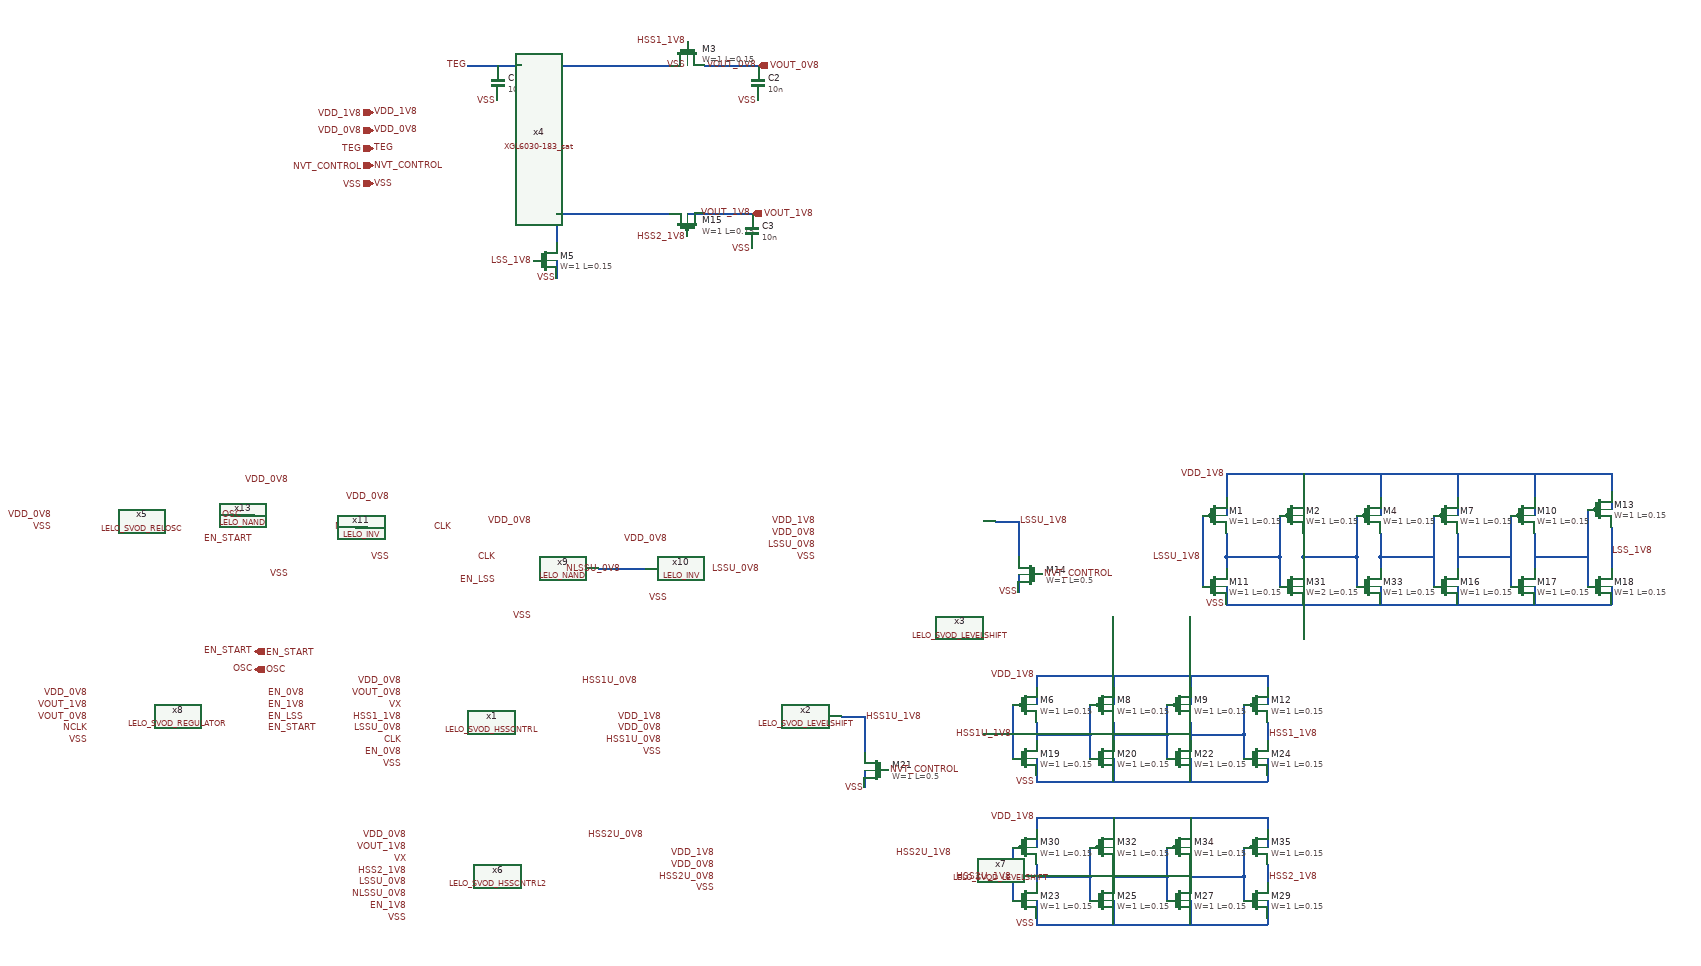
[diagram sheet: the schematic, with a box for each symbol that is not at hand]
v {xschem version=3.4.8RC file_version=1.2}
G {}
K {}
V {}
S {}
E {}
N -350 -940 -290 -940 {lab=VX}
N -480 -940 -350 -940 {lab=VX}
N -480 -940 -480 -780 {lab=VX}
N -560 -940 -540 -940 {lab=TEG}
N 650 -60 650 -30 {lab=VSS}
N 1040 -150 1040 -90 {lab=#net1}
N 1040 -60 1040 -30 {lab=VSS}
N 1000 -180 1000 -60 {lab=#net2}
N 650 -110 740 -110 {lab=#net3}
N -580 -940 -560 -940 {lab=TEG}
N 1170 -150 1170 -90 {lab=#net4}
N 1170 -60 1170 -30 {lab=VSS}
N 1130 -180 1130 -60 {lab=#net1}
N 1040 -110 1130 -110 {lab=#net1}
N 1300 -160 1300 -90 {lab=LSS_1V8}
N 1300 -60 1300 -30 {lab=VSS}
N 1260 -190 1260 -60 {lab=#net4}
N 1170 -110 1260 -110 {lab=#net4}
N -230 -940 -140 -940 {lab=VOUT_0V8}
N 650 -250 1230 -250 {lab=VDD_1V8}
N 1040 -250 1040 -210 {lab=VDD_1V8}
N 1170 -250 1170 -210 {lab=VDD_1V8}
N 1300 -250 1300 -220 {lab=VDD_1V8}
N 650 -250 650 -210 {lab=VDD_1V8}
N 650 -150 650 -110 {lab=#net3}
N 650 -110 650 -90 {lab=#net3}
N 610 -180 610 -110 {lab=LSSU_1V8}
N 610 -110 610 -60 {lab=LSSU_1V8}
N 330 90 330 110 {lab=VDD_1V8}
N 460 90 460 110 {lab=VDD_1V8}
N 330 230 330 260 {lab=VSS}
N 460 230 460 260 {lab=VSS}
N 290 140 290 190 {lab=HSS1U_1V8}
N 290 190 290 230 {lab=HSS1U_1V8}
N 330 170 330 200 {lab=#net5}
N 330 260 330 270 {lab=VSS}
N 330 190 420 190 {lab=#net5}
N 420 140 420 190 {lab=#net5}
N 420 190 420 230 {lab=#net5}
N 460 170 460 200 {lab=#net6}
N 460 260 460 270 {lab=VSS}
N 590 90 590 110 {lab=VDD_1V8}
N 590 230 590 260 {lab=VSS}
N 460 190 550 190 {lab=#net6}
N 550 140 550 190 {lab=#net6}
N 550 190 550 230 {lab=#net6}
N 590 170 590 200 {lab=#net7}
N 590 260 590 270 {lab=VSS}
N 720 90 720 110 {lab=VDD_1V8}
N 720 230 720 260 {lab=VSS}
N 680 140 680 190 {lab=#net7}
N 680 190 680 230 {lab=#net7}
N 720 170 720 200 {lab=HSS1_1V8}
N 720 260 720 270 {lab=VSS}
N 650 -210 650 -180 {lab=VDD_1V8}
N 1040 -210 1040 -180 {lab=VDD_1V8}
N 1170 -210 1170 -180 {lab=VDD_1V8}
N 1300 -220 1300 -190 {lab=VDD_1V8}
N 330 110 330 140 {lab=VDD_1V8}
N 460 110 460 140 {lab=VDD_1V8}
N 590 110 590 140 {lab=VDD_1V8}
N 780 -60 780 -30 {lab=VSS}
N 780 -110 870 -110 {lab=#net8}
N 780 -250 780 -210 {lab=VDD_1V8}
N 780 -150 780 -110 {lab=#net8}
N 780 -110 780 -90 {lab=#net8}
N 740 -180 740 -110 {lab=#net3}
N 740 -110 740 -60 {lab=#net3}
N 780 -210 780 -180 {lab=VDD_1V8}
N 910 -60 910 -30 {lab=VSS}
N 910 -110 1000 -110 {lab=#net2}
N 910 -250 910 -210 {lab=VDD_1V8}
N 910 -150 910 -110 {lab=#net2}
N 910 -110 910 -90 {lab=#net2}
N 870 -180 870 -110 {lab=#net8}
N 870 -110 870 -60 {lab=#net8}
N 910 -210 910 -180 {lab=VDD_1V8}
N 590 190 680 190 {lab=#net7}
N -480 -780 -480 -700 {lab=VX}
N -480 -700 -480 -640 {lab=VX}
N -480 -610 -480 -580 {lab=VSS}
N 330 90 720 90 {lab=VDD_1V8}
N 720 110 720 140 {lab=VDD_1V8}
N 1230 -250 1300 -250 {lab=VDD_1V8}
N 650 -30 1300 -30 {lab=VSS}
N 330 270 720 270 {lab=VSS}
N -480 -690 -290 -690 {lab=VX}
N -260 -690 -230 -690 {lab=VOUT_1V8}
N -230 -690 -150 -690 {lab=VOUT_1V8}
N 330 330 330 350 {lab=VDD_1V8}
N 460 330 460 350 {lab=VDD_1V8}
N 330 470 330 500 {lab=VSS}
N 460 470 460 500 {lab=VSS}
N 290 380 290 430 {lab=HSS2U_1V8}
N 290 430 290 470 {lab=HSS2U_1V8}
N 330 410 330 440 {lab=#net9}
N 330 500 330 510 {lab=VSS}
N 330 430 420 430 {lab=#net9}
N 420 380 420 430 {lab=#net9}
N 420 430 420 470 {lab=#net9}
N 460 410 460 440 {lab=#net10}
N 460 500 460 510 {lab=VSS}
N 590 330 590 350 {lab=VDD_1V8}
N 590 470 590 500 {lab=VSS}
N 460 430 550 430 {lab=#net10}
N 550 380 550 430 {lab=#net10}
N 550 430 550 470 {lab=#net10}
N 590 410 590 440 {lab=#net11}
N 590 500 590 510 {lab=VSS}
N 720 330 720 350 {lab=VDD_1V8}
N 720 470 720 500 {lab=VSS}
N 680 380 680 430 {lab=#net11}
N 680 430 680 470 {lab=#net11}
N 720 410 720 440 {lab=HSS2_1V8}
N 720 500 720 510 {lab=VSS}
N 330 350 330 380 {lab=VDD_1V8}
N 460 350 460 380 {lab=VDD_1V8}
N 590 350 590 380 {lab=VDD_1V8}
N 590 430 680 430 {lab=#net11}
N 330 330 720 330 {lab=VDD_1V8}
N 720 350 720 380 {lab=VDD_1V8}
N 330 510 720 510 {lab=VSS}
N -410 -90 -330 -90 {lab=NLSSU_0V8}
N -820 -160 -800 -160 {lab=NCLK}
N -630 -940 -580 -940 {lab=TEG}
N -1030 -180 -990 -180 {lab=OSC}
N 260 -170 300 -170 {lab=LSSU_1V8}
N 300 -80 300 -50 {lab=VSS}
N 300 -170 300 -110 {lab=LSSU_1V8}
N 0 160 40 160 {lab=LSSU_1V8}
N 40 250 40 280 {lab=VSS}
N 40 160 40 220 {lab=LSSU_1V8}
C {devices/lab_pin.sym} -480 -940 3 1 {name=p3 sig_type=std_logic lab=VX}
C {devices/lab_pin.sym} 1300 -120 0 1 {name=p30 sig_type=std_logic lab=LSS_1V8}
C {devices/capa.sym} -580 -910 0 1 {name=C1
m=1
value=100u
footprint=1206
device="ceramic capacitor"}
C {sky130_fd_pr/nfet_01v8_lvt.sym} -500 -610 0 0 {name=M5
W=1
L=0.15
nf=1
mult=15804
ad="expr('int((@nf + 1)/2) * @W / @nf * 0.29')"
pd="expr('2*int((@nf + 1)/2) * (@W / @nf + 0.29)')"
as="expr('int((@nf + 2)/2) * @W / @nf * 0.29')"
ps="expr('2*int((@nf + 2)/2) * (@W / @nf + 0.29)')"
nrd="expr('0.29 / @W ')" nrs="expr('0.29 / @W ')"
sa=0 sb=0 sd=0
model=nfet_01v8_lvt
spiceprefix=X
}
C {devices/lab_pin.sym} -630 -940 2 1 {name=p93 sig_type=std_logic lab=TEG}
C {devices/capa.sym} -140 -910 0 1 {name=C2
m=1
value=10n
footprint=1206
device="ceramic capacitor"}
C {devices/lab_pin.sym} -140 -940 1 0 {name=p35 sig_type=std_logic lab=VOUT_0V8}
C {sky130_fd_pr/nfet_01v8.sym} 630 -60 0 0 {name=M11
W=1
L=0.15
nf=1 
mult=1
ad="expr('int((@nf + 1)/2) * @W / @nf * 0.29')"
pd="expr('2*int((@nf + 1)/2) * (@W / @nf + 0.29)')"
as="expr('int((@nf + 2)/2) * @W / @nf * 0.29')"
ps="expr('2*int((@nf + 2)/2) * (@W / @nf + 0.29)')"
nrd="expr('0.29 / @W ')" nrs="expr('0.29 / @W ')"
sa=0 sb=0 sd=0
model=nfet_01v8
spiceprefix=X
}
C {sky130_fd_pr/nfet_01v8.sym} 1020 -60 0 0 {name=M16
W=1
L=0.15
nf=1 
mult=27
ad="expr('int((@nf + 1)/2) * @W / @nf * 0.29')"
pd="expr('2*int((@nf + 1)/2) * (@W / @nf + 0.29)')"
as="expr('int((@nf + 2)/2) * @W / @nf * 0.29')"
ps="expr('2*int((@nf + 2)/2) * (@W / @nf + 0.29)')"
nrd="expr('0.29 / @W ')" nrs="expr('0.29 / @W ')"
sa=0 sb=0 sd=0
model=nfet_01v8
spiceprefix=X
}
C {sky130_fd_pr/nfet_01v8.sym} 1150 -60 0 0 {name=M17
W=1
L=0.15
nf=1 
mult=81
ad="expr('int((@nf + 1)/2) * @W / @nf * 0.29')"
pd="expr('2*int((@nf + 1)/2) * (@W / @nf + 0.29)')"
as="expr('int((@nf + 2)/2) * @W / @nf * 0.29')"
ps="expr('2*int((@nf + 2)/2) * (@W / @nf + 0.29)')"
nrd="expr('0.29 / @W ')" nrs="expr('0.29 / @W ')"
sa=0 sb=0 sd=0
model=nfet_01v8
spiceprefix=X
}
C {sky130_fd_pr/nfet_01v8.sym} 1280 -60 0 0 {name=M18
W=1
L=0.15
nf=1 
mult=243
ad="expr('int((@nf + 1)/2) * @W / @nf * 0.29')"
pd="expr('2*int((@nf + 1)/2) * (@W / @nf + 0.29)')"
as="expr('int((@nf + 2)/2) * @W / @nf * 0.29')"
ps="expr('2*int((@nf + 2)/2) * (@W / @nf + 0.29)')"
nrd="expr('0.29 / @W ')" nrs="expr('0.29 / @W ')"
sa=0 sb=0 sd=0
model=nfet_01v8
spiceprefix=X
}
C {sky130_fd_pr/nfet_01v8.sym} 310 230 0 0 {name=M19
W=1
L=0.15
nf=1 
mult=1
ad="expr('int((@nf + 1)/2) * @W / @nf * 0.29')"
pd="expr('2*int((@nf + 1)/2) * (@W / @nf + 0.29)')"
as="expr('int((@nf + 2)/2) * @W / @nf * 0.29')"
ps="expr('2*int((@nf + 2)/2) * (@W / @nf + 0.29)')"
nrd="expr('0.29 / @W ')" nrs="expr('0.29 / @W ')"
sa=0 sb=0 sd=0
model=nfet_01v8
spiceprefix=X
}
C {sky130_fd_pr/nfet_01v8.sym} 440 230 0 0 {name=M20
W=1
L=0.15
nf=1 
mult=3
ad="expr('int((@nf + 1)/2) * @W / @nf * 0.29')"
pd="expr('2*int((@nf + 1)/2) * (@W / @nf + 0.29)')"
as="expr('int((@nf + 2)/2) * @W / @nf * 0.29')"
ps="expr('2*int((@nf + 2)/2) * (@W / @nf + 0.29)')"
nrd="expr('0.29 / @W ')" nrs="expr('0.29 / @W ')"
sa=0 sb=0 sd=0
model=nfet_01v8
spiceprefix=X
}
C {sky130_fd_pr/nfet_01v8.sym} 570 230 0 0 {name=M22
W=1
L=0.15
nf=1 
mult=9
ad="expr('int((@nf + 1)/2) * @W / @nf * 0.29')"
pd="expr('2*int((@nf + 1)/2) * (@W / @nf + 0.29)')"
as="expr('int((@nf + 2)/2) * @W / @nf * 0.29')"
ps="expr('2*int((@nf + 2)/2) * (@W / @nf + 0.29)')"
nrd="expr('0.29 / @W ')" nrs="expr('0.29 / @W ')"
sa=0 sb=0 sd=0
model=nfet_01v8
spiceprefix=X
}
C {sky130_fd_pr/nfet_01v8.sym} 700 230 0 0 {name=M24
W=1
L=0.15
nf=1 
mult=27
ad="expr('int((@nf + 1)/2) * @W / @nf * 0.29')"
pd="expr('2*int((@nf + 1)/2) * (@W / @nf + 0.29)')"
as="expr('int((@nf + 2)/2) * @W / @nf * 0.29')"
ps="expr('2*int((@nf + 2)/2) * (@W / @nf + 0.29)')"
nrd="expr('0.29 / @W ')" nrs="expr('0.29 / @W ')"
sa=0 sb=0 sd=0
model=nfet_01v8
spiceprefix=X
}
C {sky130_fd_pr/nfet_01v8.sym} 760 -60 0 0 {name=M31
W=2
L=0.15
nf=1 
mult=3
ad="expr('int((@nf + 1)/2) * @W / @nf * 0.29')"
pd="expr('2*int((@nf + 1)/2) * (@W / @nf + 0.29)')"
as="expr('int((@nf + 2)/2) * @W / @nf * 0.29')"
ps="expr('2*int((@nf + 2)/2) * (@W / @nf + 0.29)')"
nrd="expr('0.29 / @W ')" nrs="expr('0.29 / @W ')"
sa=0 sb=0 sd=0
model=nfet_01v8
spiceprefix=X
}
C {sky130_fd_pr/nfet_01v8.sym} 890 -60 0 0 {name=M33
W=1
L=0.15
nf=1 
mult=9
ad="expr('int((@nf + 1)/2) * @W / @nf * 0.29')"
pd="expr('2*int((@nf + 1)/2) * (@W / @nf + 0.29)')"
as="expr('int((@nf + 2)/2) * @W / @nf * 0.29')"
ps="expr('2*int((@nf + 2)/2) * (@W / @nf + 0.29)')"
nrd="expr('0.29 / @W ')" nrs="expr('0.29 / @W ')"
sa=0 sb=0 sd=0
model=nfet_01v8
spiceprefix=X
}
C {devices/lab_pin.sym} -260 -980 1 0 {name=p101 sig_type=std_logic lab=HSS1_1V8}
C {sky130_fd_pr/nfet_01v8_lvt.sym} -260 -960 1 0 {name=M3
W=1
L=0.15
nf=1
mult=3244
ad="expr('int((@nf + 1)/2) * @W / @nf * 0.29')"
pd="expr('2*int((@nf + 1)/2) * (@W / @nf + 0.29)')"
as="expr('int((@nf + 2)/2) * @W / @nf * 0.29')"
ps="expr('2*int((@nf + 2)/2) * (@W / @nf + 0.29)')"
nrd="expr('0.29 / @W ')" nrs="expr('0.29 / @W ')"
sa=0 sb=0 sd=0
model=nfet_01v8_lvt
spiceprefix=X
}
C {devices/lab_pin.sym} -220 -90 0 1 {name=p10 sig_type=std_logic lab=LSSU_0V8}
C {LELO_SVOD_SKY130A/LELO_SVOD_HSSCNTRL.sym} -590 170 0 0 {name=x1}
C {devices/lab_pin.sym} -440 100 2 0 {name=p22 sig_type=std_logic lab=HSS1U_0V8}
C {devices/lab_pin.sym} -740 140 2 1 {name=p26 sig_type=std_logic lab=VX}
C {devices/lab_pin.sym} -740 120 0 0 {name=p27 sig_type=std_logic lab=VOUT_0V8}
C {LELO_SVOD_SKY130A/LELO_SVOD_LEVELSHIFT.sym} -150 190 0 0 {name=x2}
C {LELO_SVOD_SKY130A/LELO_SVOD_LEVELSHIFT.sym} 110 -140 0 0 {name=x3}
C {devices/lab_pin.sym} 40 160 2 0 {name=p8 sig_type=std_logic lab=HSS1U_1V8}
C {devices/lab_pin.sym} 300 -170 0 1 {name=p23 sig_type=std_logic lab=LSSU_1V8}
C {sky130_fd_pr/pfet_01v8_hvt.sym} 310 140 0 0 {name=M6
W=1
L=0.15
nf=1
mult=1
ad="expr('int((@nf + 1)/2) * @W / @nf * 0.29')"
pd="expr('2*int((@nf + 1)/2) * (@W / @nf + 0.29)')"
as="expr('int((@nf + 2)/2) * @W / @nf * 0.29')"
ps="expr('2*int((@nf + 2)/2) * (@W / @nf + 0.29)')"
nrd="expr('0.29 / @W ')" nrs="expr('0.29 / @W ')"
sa=0 sb=0 sd=0
model=pfet_01v8_hvt
spiceprefix=X
}
C {sky130_fd_pr/pfet_01v8_hvt.sym} 440 140 0 0 {name=M8
W=1
L=0.15
nf=1
mult=3
ad="expr('int((@nf + 1)/2) * @W / @nf * 0.29')"
pd="expr('2*int((@nf + 1)/2) * (@W / @nf + 0.29)')"
as="expr('int((@nf + 2)/2) * @W / @nf * 0.29')"
ps="expr('2*int((@nf + 2)/2) * (@W / @nf + 0.29)')"
nrd="expr('0.29 / @W ')" nrs="expr('0.29 / @W ')"
sa=0 sb=0 sd=0
model=pfet_01v8_hvt
spiceprefix=X
}
C {sky130_fd_pr/pfet_01v8_hvt.sym} 570 140 0 0 {name=M9
W=1
L=0.15
nf=1
mult=9
ad="expr('int((@nf + 1)/2) * @W / @nf * 0.29')"
pd="expr('2*int((@nf + 1)/2) * (@W / @nf + 0.29)')"
as="expr('int((@nf + 2)/2) * @W / @nf * 0.29')"
ps="expr('2*int((@nf + 2)/2) * (@W / @nf + 0.29)')"
nrd="expr('0.29 / @W ')" nrs="expr('0.29 / @W ')"
sa=0 sb=0 sd=0
model=pfet_01v8_hvt
spiceprefix=X
}
C {sky130_fd_pr/pfet_01v8_hvt.sym} 700 140 0 0 {name=M12
W=1
L=0.15
nf=1
mult=27
ad="expr('int((@nf + 1)/2) * @W / @nf * 0.29')"
pd="expr('2*int((@nf + 1)/2) * (@W / @nf + 0.29)')"
as="expr('int((@nf + 2)/2) * @W / @nf * 0.29')"
ps="expr('2*int((@nf + 2)/2) * (@W / @nf + 0.29)')"
nrd="expr('0.29 / @W ')" nrs="expr('0.29 / @W ')"
sa=0 sb=0 sd=0
model=pfet_01v8_hvt
spiceprefix=X
}
C {sky130_fd_pr/pfet_01v8_hvt.sym} 630 -180 0 0 {name=M1
W=1
L=0.15
nf=1
mult=1
ad="expr('int((@nf + 1)/2) * @W / @nf * 0.29')"
pd="expr('2*int((@nf + 1)/2) * (@W / @nf + 0.29)')"
as="expr('int((@nf + 2)/2) * @W / @nf * 0.29')"
ps="expr('2*int((@nf + 2)/2) * (@W / @nf + 0.29)')"
nrd="expr('0.29 / @W ')" nrs="expr('0.29 / @W ')"
sa=0 sb=0 sd=0
model=pfet_01v8_hvt
spiceprefix=X
}
C {sky130_fd_pr/pfet_01v8_hvt.sym} 760 -180 0 0 {name=M2
W=1
L=0.15
nf=1
mult=3
ad="expr('int((@nf + 1)/2) * @W / @nf * 0.29')"
pd="expr('2*int((@nf + 1)/2) * (@W / @nf + 0.29)')"
as="expr('int((@nf + 2)/2) * @W / @nf * 0.29')"
ps="expr('2*int((@nf + 2)/2) * (@W / @nf + 0.29)')"
nrd="expr('0.29 / @W ')" nrs="expr('0.29 / @W ')"
sa=0 sb=0 sd=0
model=pfet_01v8_hvt
spiceprefix=X
}
C {sky130_fd_pr/pfet_01v8_hvt.sym} 890 -180 0 0 {name=M4
W=1
L=0.15
nf=1
mult=9
ad="expr('int((@nf + 1)/2) * @W / @nf * 0.29')"
pd="expr('2*int((@nf + 1)/2) * (@W / @nf + 0.29)')"
as="expr('int((@nf + 2)/2) * @W / @nf * 0.29')"
ps="expr('2*int((@nf + 2)/2) * (@W / @nf + 0.29)')"
nrd="expr('0.29 / @W ')" nrs="expr('0.29 / @W ')"
sa=0 sb=0 sd=0
model=pfet_01v8_hvt
spiceprefix=X
}
C {sky130_fd_pr/pfet_01v8_hvt.sym} 1020 -180 0 0 {name=M7
W=1
L=0.15
nf=1
mult=27
ad="expr('int((@nf + 1)/2) * @W / @nf * 0.29')"
pd="expr('2*int((@nf + 1)/2) * (@W / @nf + 0.29)')"
as="expr('int((@nf + 2)/2) * @W / @nf * 0.29')"
ps="expr('2*int((@nf + 2)/2) * (@W / @nf + 0.29)')"
nrd="expr('0.29 / @W ')" nrs="expr('0.29 / @W ')"
sa=0 sb=0 sd=0
model=pfet_01v8_hvt
spiceprefix=X
}
C {sky130_fd_pr/pfet_01v8_hvt.sym} 1150 -180 0 0 {name=M10
W=1
L=0.15
nf=1
mult=81
ad="expr('int((@nf + 1)/2) * @W / @nf * 0.29')"
pd="expr('2*int((@nf + 1)/2) * (@W / @nf + 0.29)')"
as="expr('int((@nf + 2)/2) * @W / @nf * 0.29')"
ps="expr('2*int((@nf + 2)/2) * (@W / @nf + 0.29)')"
nrd="expr('0.29 / @W ')" nrs="expr('0.29 / @W ')"
sa=0 sb=0 sd=0
model=pfet_01v8_hvt
spiceprefix=X
}
C {sky130_fd_pr/pfet_01v8_hvt.sym} 1280 -190 0 0 {name=M13
W=1
L=0.15
nf=1
mult=243
ad="expr('int((@nf + 1)/2) * @W / @nf * 0.29')"
pd="expr('2*int((@nf + 1)/2) * (@W / @nf + 0.29)')"
as="expr('int((@nf + 2)/2) * @W / @nf * 0.29')"
ps="expr('2*int((@nf + 2)/2) * (@W / @nf + 0.29)')"
nrd="expr('0.29 / @W ')" nrs="expr('0.29 / @W ')"
sa=0 sb=0 sd=0
model=pfet_01v8_hvt
spiceprefix=X
}
C {devices/lab_pin.sym} -300 200 2 1 {name=p5 sig_type=std_logic lab=HSS1U_0V8}
C {devices/lab_pin.sym} 290 190 2 1 {name=p9 sig_type=std_logic lab=HSS1U_1V8}
C {devices/lab_pin.sym} -1330 -180 0 0 {name=p17 sig_type=std_logic lab=VDD_0V8}
C {devices/lab_pin.sym} -740 100 0 0 {name=p21 sig_type=std_logic lab=VDD_0V8}
C {devices/lab_pin.sym} -300 180 0 0 {name=p28 sig_type=std_logic lab=VDD_0V8}
C {devices/lab_pin.sym} -40 -150 0 0 {name=p29 sig_type=std_logic lab=VDD_0V8}
C {devices/lab_pin.sym} -300 160 0 0 {name=p31 sig_type=std_logic lab=VDD_1V8}
C {devices/lab_pin.sym} -40 -170 0 0 {name=p32 sig_type=std_logic lab=VDD_1V8}
C {devices/lab_pin.sym} 330 90 0 0 {name=p33 sig_type=std_logic lab=VDD_1V8}
C {devices/lab_pin.sym} 650 -250 0 0 {name=p34 sig_type=std_logic lab=VDD_1V8}
C {devices/lab_pin.sym} -520 -610 0 0 {name=p36 sig_type=std_logic lab=LSS_1V8}
C {devices/lab_pin.sym} -40 -130 0 0 {name=p37 sig_type=std_logic lab=LSSU_0V8}
C {devices/lab_pin.sym} 610 -110 0 0 {name=p38 sig_type=std_logic lab=LSSU_1V8}
C {devices/lab_pin.sym} 720 190 2 0 {name=p39 sig_type=std_logic lab=HSS1_1V8}
C {devices/ipin.sym} -790 -740 0 0 {name=p40 lab=VSS}
C {devices/lab_pin.sym} -790 -740 2 0 {name=p41 sig_type=std_logic lab=VSS}
C {devices/lab_pin.sym} -740 180 0 0 {name=p25 sig_type=std_logic lab=LSSU_0V8}
C {devices/lab_pin.sym} -740 160 0 0 {name=p49 sig_type=std_logic lab=HSS1_1V8}
C {devices/lab_pin.sym} -760 -210 1 0 {name=p51 sig_type=std_logic lab=VDD_0V8}
C {LELO_SVOD_SKY130A/XGL6030-183_sat.sym} -510 -940 1 0 {name=x4}
C {LELO_SVOD_SKY130A/LELO_SVOD_RELOSC.sym} -1180 -170 0 0 {name=x5}
C {sky130_fd_pr/pfet_01v8.sym} -260 -670 1 1 {name=M15
W=1
L=0.15
nf=1
mult=481
ad="expr('int((@nf + 1)/2) * @W / @nf * 0.29')"
pd="expr('2*int((@nf + 1)/2) * (@W / @nf + 0.29)')"
as="expr('int((@nf + 2)/2) * @W / @nf * 0.29')"
ps="expr('2*int((@nf + 2)/2) * (@W / @nf + 0.29)')"
nrd="expr('0.29 / @W ')" nrs="expr('0.29 / @W ')"
sa=0 sb=0 sd=0
model=pfet_01v8
spiceprefix=X
}
C {devices/capa.sym} -150 -660 0 1 {name=C3
m=1
value=10n
footprint=1206
device="ceramic capacitor"}
C {devices/lab_pin.sym} -150 -690 1 0 {name=p45 sig_type=std_logic lab=VOUT_1V8}
C {LELO_SVOD_SKY130A/LELO_SVOD_HSSCNTRL2.sym} -580 430 0 0 {name=x6}
C {devices/lab_pin.sym} -730 400 2 1 {name=p48 sig_type=std_logic lab=VX}
C {devices/lab_pin.sym} -730 360 0 0 {name=p50 sig_type=std_logic lab=VDD_0V8}
C {devices/lab_pin.sym} -730 380 0 0 {name=p53 sig_type=std_logic lab=VOUT_1V8}
C {devices/lab_pin.sym} -730 440 0 0 {name=p54 sig_type=std_logic lab=LSSU_0V8}
C {devices/lab_pin.sym} -430 360 2 0 {name=p57 sig_type=std_logic lab=HSS2U_0V8}
C {LELO_SVOD_SKY130A/LELO_SVOD_LEVELSHIFT.sym} -60 420 0 0 {name=x7}
C {devices/lab_pin.sym} 90 390 2 0 {name=p58 sig_type=std_logic lab=HSS2U_1V8}
C {devices/lab_pin.sym} -210 410 0 0 {name=p61 sig_type=std_logic lab=VDD_0V8}
C {devices/lab_pin.sym} -210 390 0 0 {name=p62 sig_type=std_logic lab=VDD_1V8}
C {devices/lab_pin.sym} -210 430 2 1 {name=p60 sig_type=std_logic lab=HSS2U_0V8}
C {sky130_fd_pr/nfet_01v8.sym} 310 470 0 0 {name=M23
W=1
L=0.15
nf=1 
mult=1
ad="expr('int((@nf + 1)/2) * @W / @nf * 0.29')"
pd="expr('2*int((@nf + 1)/2) * (@W / @nf + 0.29)')"
as="expr('int((@nf + 2)/2) * @W / @nf * 0.29')"
ps="expr('2*int((@nf + 2)/2) * (@W / @nf + 0.29)')"
nrd="expr('0.29 / @W ')" nrs="expr('0.29 / @W ')"
sa=0 sb=0 sd=0
model=nfet_01v8
spiceprefix=X
}
C {sky130_fd_pr/nfet_01v8.sym} 440 470 0 0 {name=M25
W=1
L=0.15
nf=1 
mult=3
ad="expr('int((@nf + 1)/2) * @W / @nf * 0.29')"
pd="expr('2*int((@nf + 1)/2) * (@W / @nf + 0.29)')"
as="expr('int((@nf + 2)/2) * @W / @nf * 0.29')"
ps="expr('2*int((@nf + 2)/2) * (@W / @nf + 0.29)')"
nrd="expr('0.29 / @W ')" nrs="expr('0.29 / @W ')"
sa=0 sb=0 sd=0
model=nfet_01v8
spiceprefix=X
}
C {sky130_fd_pr/nfet_01v8.sym} 570 470 0 0 {name=M27
W=1
L=0.15
nf=1 
mult=9
ad="expr('int((@nf + 1)/2) * @W / @nf * 0.29')"
pd="expr('2*int((@nf + 1)/2) * (@W / @nf + 0.29)')"
as="expr('int((@nf + 2)/2) * @W / @nf * 0.29')"
ps="expr('2*int((@nf + 2)/2) * (@W / @nf + 0.29)')"
nrd="expr('0.29 / @W ')" nrs="expr('0.29 / @W ')"
sa=0 sb=0 sd=0
model=nfet_01v8
spiceprefix=X
}
C {sky130_fd_pr/nfet_01v8.sym} 700 470 0 0 {name=M29
W=1
L=0.15
nf=1 
mult=27
ad="expr('int((@nf + 1)/2) * @W / @nf * 0.29')"
pd="expr('2*int((@nf + 1)/2) * (@W / @nf + 0.29)')"
as="expr('int((@nf + 2)/2) * @W / @nf * 0.29')"
ps="expr('2*int((@nf + 2)/2) * (@W / @nf + 0.29)')"
nrd="expr('0.29 / @W ')" nrs="expr('0.29 / @W ')"
sa=0 sb=0 sd=0
model=nfet_01v8
spiceprefix=X
}
C {sky130_fd_pr/pfet_01v8_hvt.sym} 310 380 0 0 {name=M30
W=1
L=0.15
nf=1
mult=1
ad="expr('int((@nf + 1)/2) * @W / @nf * 0.29')"
pd="expr('2*int((@nf + 1)/2) * (@W / @nf + 0.29)')"
as="expr('int((@nf + 2)/2) * @W / @nf * 0.29')"
ps="expr('2*int((@nf + 2)/2) * (@W / @nf + 0.29)')"
nrd="expr('0.29 / @W ')" nrs="expr('0.29 / @W ')"
sa=0 sb=0 sd=0
model=pfet_01v8_hvt
spiceprefix=X
}
C {sky130_fd_pr/pfet_01v8_hvt.sym} 440 380 0 0 {name=M32
W=1
L=0.15
nf=1
mult=3
ad="expr('int((@nf + 1)/2) * @W / @nf * 0.29')"
pd="expr('2*int((@nf + 1)/2) * (@W / @nf + 0.29)')"
as="expr('int((@nf + 2)/2) * @W / @nf * 0.29')"
ps="expr('2*int((@nf + 2)/2) * (@W / @nf + 0.29)')"
nrd="expr('0.29 / @W ')" nrs="expr('0.29 / @W ')"
sa=0 sb=0 sd=0
model=pfet_01v8_hvt
spiceprefix=X
}
C {sky130_fd_pr/pfet_01v8_hvt.sym} 570 380 0 0 {name=M34
W=1
L=0.15
nf=1
mult=9
ad="expr('int((@nf + 1)/2) * @W / @nf * 0.29')"
pd="expr('2*int((@nf + 1)/2) * (@W / @nf + 0.29)')"
as="expr('int((@nf + 2)/2) * @W / @nf * 0.29')"
ps="expr('2*int((@nf + 2)/2) * (@W / @nf + 0.29)')"
nrd="expr('0.29 / @W ')" nrs="expr('0.29 / @W ')"
sa=0 sb=0 sd=0
model=pfet_01v8_hvt
spiceprefix=X
}
C {sky130_fd_pr/pfet_01v8_hvt.sym} 700 380 0 0 {name=M35
W=1
L=0.15
nf=1
mult=27
ad="expr('int((@nf + 1)/2) * @W / @nf * 0.29')"
pd="expr('2*int((@nf + 1)/2) * (@W / @nf + 0.29)')"
as="expr('int((@nf + 2)/2) * @W / @nf * 0.29')"
ps="expr('2*int((@nf + 2)/2) * (@W / @nf + 0.29)')"
nrd="expr('0.29 / @W ')" nrs="expr('0.29 / @W ')"
sa=0 sb=0 sd=0
model=pfet_01v8_hvt
spiceprefix=X
}
C {devices/lab_pin.sym} 330 330 0 0 {name=p65 sig_type=std_logic lab=VDD_1V8}
C {devices/lab_pin.sym} 720 430 2 0 {name=p66 sig_type=std_logic lab=HSS2_1V8}
C {devices/lab_pin.sym} 290 430 2 1 {name=p64 sig_type=std_logic lab=HSS2U_1V8}
C {devices/lab_pin.sym} -730 420 2 1 {name=p67 sig_type=std_logic lab=HSS2_1V8}
C {devices/lab_pin.sym} -260 -650 1 1 {name=p68 sig_type=std_logic lab=HSS2_1V8}
C {LELO_SVOD_SKY130A/LELO_SVOD_REGULATOR.sym} -1120 160 0 0 {name=x8}
C {devices/lab_pin.sym} -970 120 0 1 {name=p18 sig_type=std_logic lab=EN_0V8}
C {devices/lab_pin.sym} -740 220 0 0 {name=p55 sig_type=std_logic lab=EN_0V8}
C {devices/lab_pin.sym} -970 140 0 1 {name=p69 sig_type=std_logic lab=EN_1V8}
C {devices/lab_pin.sym} -730 480 0 0 {name=p70 sig_type=std_logic lab=EN_1V8}
C {devices/lab_pin.sym} -1270 160 0 0 {name=p71 sig_type=std_logic lab=VOUT_0V8}
C {devices/lab_pin.sym} -1270 140 0 0 {name=p72 sig_type=std_logic lab=VOUT_1V8}
C {devices/lab_pin.sym} -1270 120 0 0 {name=p46 sig_type=std_logic lab=VDD_0V8}
C {devices/lab_pin.sym} -810 -160 3 1 {name=p76 sig_type=std_logic lab=NCLK}
C {LELO_SVOD_SKY130A/LELO_NAND.sym} -500 -90 0 0 {name=x9}
C {LELO_SVOD_SKY130A/LELO_INV.sym} -270 -90 0 0 {name=x10}
C {devices/lab_pin.sym} -520 -170 0 0 {name=p81 sig_type=std_logic lab=VDD_0V8}
C {devices/lab_pin.sym} -290 -140 0 0 {name=p82 sig_type=std_logic lab=VDD_0V8}
C {devices/lab_pin.sym} -970 160 0 1 {name=p85 sig_type=std_logic lab=EN_LSS}
C {devices/lab_pin.sym} -580 -70 0 0 {name=p83 sig_type=std_logic lab=EN_LSS}
C {devices/lab_pin.sym} -1270 180 0 0 {name=p74 sig_type=std_logic lab=NCLK}
C {devices/lab_pin.sym} -690 -160 0 1 {name=p84 sig_type=std_logic lab=CLK}
C {devices/lab_pin.sym} -580 -110 0 0 {name=p78 sig_type=std_logic lab=CLK}
C {devices/lab_pin.sym} -370 -90 1 1 {name=p86 sig_type=std_logic lab=NLSSU_0V8}
C {devices/lab_pin.sym} -730 460 2 1 {name=p88 sig_type=std_logic lab=NLSSU_0V8}
C {devices/lab_pin.sym} -740 200 0 0 {name=p87 sig_type=std_logic lab=CLK}
C {devices/lab_pin.sym} -480 -580 3 0 {name=p1 sig_type=std_logic lab=VSS}
C {devices/lab_pin.sym} -150 -630 3 0 {name=p4 sig_type=std_logic lab=VSS}
C {devices/lab_pin.sym} -140 -880 3 0 {name=p11 sig_type=std_logic lab=VSS}
C {devices/lab_pin.sym} -520 -10 3 0 {name=p12 sig_type=std_logic lab=VSS}
C {devices/lab_pin.sym} -760 -110 3 0 {name=p13 sig_type=std_logic lab=VSS}
C {LELO_SVOD_SKY130A/LELO_INV.sym} -740 -160 0 0 {name=x11}
C {devices/lab_pin.sym} -1270 200 0 0 {name=p14 sig_type=std_logic lab=VSS}
C {devices/lab_pin.sym} -740 240 0 0 {name=p15 sig_type=std_logic lab=VSS}
C {devices/lab_pin.sym} -730 500 0 0 {name=p16 sig_type=std_logic lab=VSS}
C {devices/lab_pin.sym} -210 450 0 0 {name=p19 sig_type=std_logic lab=VSS}
C {devices/lab_pin.sym} -300 220 0 0 {name=p20 sig_type=std_logic lab=VSS}
C {devices/lab_pin.sym} -40 -110 0 0 {name=p24 sig_type=std_logic lab=VSS}
C {devices/lab_pin.sym} 330 270 0 0 {name=p42 sig_type=std_logic lab=VSS}
C {devices/lab_pin.sym} 330 510 0 0 {name=p43 sig_type=std_logic lab=VSS}
C {devices/lab_pin.sym} 650 -30 0 0 {name=p44 sig_type=std_logic lab=VSS}
C {devices/lab_pin.sym} -1330 -160 0 0 {name=p47 sig_type=std_logic lab=VSS}
C {devices/lab_pin.sym} -580 -880 3 0 {name=p7 sig_type=std_logic lab=VSS}
C {devices/lab_pin.sym} -260 -940 3 0 {name=p6 sig_type=std_logic lab=VSS}
C {devices/lab_pin.sym} -290 -40 3 0 {name=p52 sig_type=std_logic lab=VSS}
C {devices/ipin.sym} -790 -800 0 0 {name=p56 lab=TEG}
C {devices/lab_pin.sym} -790 -800 2 0 {name=p59 sig_type=std_logic lab=TEG}
C {devices/lab_pin.sym} -790 -830 0 1 {name=p63 sig_type=std_logic lab=VDD_0V8}
C {devices/ipin.sym} -790 -830 0 0 {name=p73 lab=VDD_0V8}
C {devices/lab_pin.sym} -790 -860 0 1 {name=p75 sig_type=std_logic lab=VDD_1V8}
C {devices/ipin.sym} -790 -860 0 0 {name=p77 lab=VDD_1V8}
C {devices/opin.sym} -140 -940 0 0 {name=p2 lab=VOUT_0V8}
C {devices/opin.sym} -150 -690 0 0 {name=p79 lab=VOUT_1V8}
C {LELO_SVOD_SKY130A/LELO_NAND.sym} -910 -160 0 0 {name=x13}
C {devices/lab_pin.sym} -930 -240 0 0 {name=p80 sig_type=std_logic lab=VDD_0V8}
C {devices/lab_pin.sym} -930 -80 3 0 {name=p89 sig_type=std_logic lab=VSS}
C {devices/lab_pin.sym} -1010 -180 3 1 {name=p90 sig_type=std_logic lab=OSC}
C {devices/lab_pin.sym} -990 -140 0 0 {name=p91 sig_type=std_logic lab=EN_START}
C {devices/lab_pin.sym} -970 180 0 1 {name=p92 sig_type=std_logic lab=EN_START}
C {devices/opin.sym} -990 50 0 0 {name=p94 lab=EN_START}
C {devices/lab_pin.sym} -990 50 0 0 {name=p95 sig_type=std_logic lab=EN_START}
C {devices/opin.sym} -990 80 0 0 {name=p96 lab=OSC}
C {devices/lab_pin.sym} -990 80 0 0 {name=p97 sig_type=std_logic lab=OSC}
C {sky130_fd_pr/nfet_03v3_nvt.sym} 320 -80 0 1 {name=M14
W=1
L=0.5
nf=1
mult=1
ad="expr('int((@nf + 1)/2) * @W / @nf * 0.29')"
pd="expr('2*int((@nf + 1)/2) * (@W / @nf + 0.29)')"
as="expr('int((@nf + 2)/2) * @W / @nf * 0.29')"
ps="expr('2*int((@nf + 2)/2) * (@W / @nf + 0.29)')"
nrd="expr('0.29 / @W ')" nrs="expr('0.29 / @W ')"
sa=0 sb=0 sd=0
model=nfet_03v3_nvt
spiceprefix=X
}
C {devices/lab_pin.sym} 300 -50 0 0 {name=p98 sig_type=std_logic lab=VSS}
C {devices/ipin.sym} -790 -770 0 0 {name=p99 lab=NVT_CONTROL}
C {devices/lab_pin.sym} -790 -770 2 0 {name=p100 sig_type=std_logic lab=NVT_CONTROL}
C {devices/lab_pin.sym} 340 -80 2 0 {name=p102 sig_type=std_logic lab=NVT_CONTROL}
C {sky130_fd_pr/nfet_03v3_nvt.sym} 60 250 0 1 {name=M21
W=1
L=0.5
nf=1
mult=1
ad="expr('int((@nf + 1)/2) * @W / @nf * 0.29')"
pd="expr('2*int((@nf + 1)/2) * (@W / @nf + 0.29)')"
as="expr('int((@nf + 2)/2) * @W / @nf * 0.29')"
ps="expr('2*int((@nf + 2)/2) * (@W / @nf + 0.29)')"
nrd="expr('0.29 / @W ')" nrs="expr('0.29 / @W ')"
sa=0 sb=0 sd=0
model=nfet_03v3_nvt
spiceprefix=X
}
C {devices/lab_pin.sym} 40 280 0 0 {name=p104 sig_type=std_logic lab=VSS}
C {devices/lab_pin.sym} 80 250 2 0 {name=p105 sig_type=std_logic lab=NVT_CONTROL}
